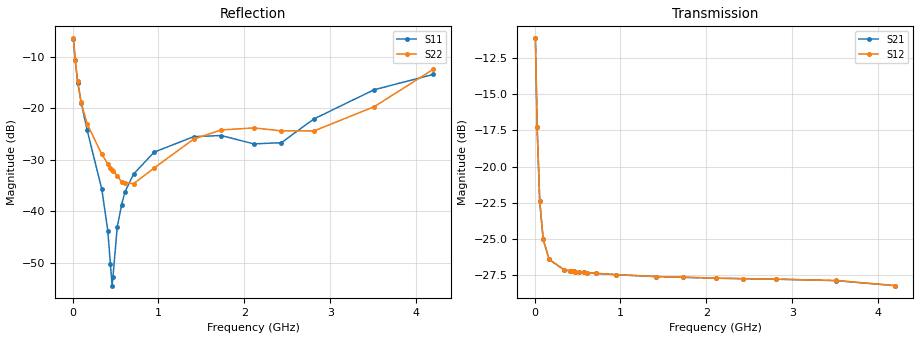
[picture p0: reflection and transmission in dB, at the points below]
! Integrated Device Technology
! Corporate Headquarters
! 6024 Silver Creek Valley Road
! San Jose, CA 95138  USA
! Phone:  1-408-284-8200
! Toll Free:  1-800-223-1366
! Webpage:  http://www.idt.com/
! Timing and RF Division
! 515 Groton Road, Suite 102
! Westford, MA 01886-6024
! Device:  F1950
! Description: 7-bit 0.25 dB Digital Step Attenuator
! Frequency:  150.0 -  4000.00 MHz
! Package:  4x4 mm Thin QFN Plastic Package: 24 pin
! Ports:  2 RF, 12 DC
!  Pin  1  = D0
!  Pin  2  = VDD
!  Pin  3  = Vmode
!  Pin  4  = GND
!  Pin  5  = RF1  =  Port 1
!  Pin  6  = GND
!  Pin  7  = GND
!  Pin  8  = GND
!  Pin  9  = GND
!  Pin 10  = GND
!  Pin 11  = GND
!  Pin 12  = GND
!  Pin 13  = GND
!  Pin 14  = RF2  =  Port 2
!  Pin 15  = GND
!  Pin 16  = LE
!  Pin 17  = CLK
!  Pin 18  = DATE
!  Pin 19  = D6
!  Pin 20  = D5
!  Pin 21  = D4
!  Pin 22  = D3
!  Pin 23  = D2
!  Pin 24  = D1
! State:  106
! Atten State:  26.50 dB
! Voltage:  +5.00 Volts
! Current:  Not Measured mA
! Data:  The device was measured on a the F195X evaluation board which has
!  individual transmission lines to the RF pins.  Data was collected
!  using a calibrated network analyzer.  The evaluation board was
!  de-embedded using a TRL calibration technique.
!  The reference plane is the edge of the package pin.
! Misc:  Board 2019
!  Action Tracker AT0250
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# GHz S dB R 50
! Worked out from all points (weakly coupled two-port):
!   420 points, 10 MHz to 4.2 GHz, reference 50 ohm
!   highest |S21| = -11.15 dB at 10 MHz (marker M1); lowest = -28.2 dB at 4.2 GHz (marker M2)
!   lowest |S11| = -54.4 dB at 460 MHz (marker M3), VSWR 1.00, Z = 49.8 - j0.079 ohm
!   |S11| at or under -10 dB: 26.72 MHz to end of sweep
!   |S22| runs from -34.9 to -6.5 dB; largest |S21 - S12| = 8.2e-05
!   S11 on the Smith chart (normalised r, x): 10 MHz: 2.02, -1.12; 30 MHz: 1.28, -0.64; 60 MHz: 1.11, -0.36; 410 MHz: 1.00, -0.01; 4.2 GHz: 0.68, +0.17
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0.01  -6.56 -27.3  -11.15 -36.1  -11.15 -36.1  -6.45 -28.4
0.03  -10.62 -50.4  -17.28 -55.1  -17.28 -55.1  -10.55 -52.0
0.06  -15.02 -63.5  -22.37 -50.2  -22.36 -50.2  -14.80 -65.1
0.1  -18.89 -70.4  -25.00 -38.4  -25.00 -38.4  -18.87 -70.8
0.17  -24.27 -72.1  -26.40 -26.4  -26.40 -26.4  -23.06 -76.7
0.34  -35.65 -71.6  -27.10 -16.9  -27.10 -16.9  -28.90 -85.6
0.41  -43.71 -80.3  -27.19 -15.5  -27.19 -15.5  -30.80 -88.8
0.44  -50.12 -101.8  -27.21 -15.1  -27.21 -15.2  -31.60 -92.9
0.46  -54.38 -155.5  -27.23 -14.9  -27.23 -15.0  -32.00 -96.3
0.47  -52.68 173.1  -27.24 -14.9  -27.24 -14.9  -32.15 -97.9
0.52  -43.02 142.3  -27.27 -14.5  -27.27 -14.6  -33.06 -102.8
0.57  -38.75 136.6  -27.30 -14.4  -27.29 -14.4  -34.28 -112.7
0.61  -36.17 137.8  -27.32 -14.3  -27.32 -14.3  -34.40 -120.9
0.71  -32.75 138.7  -27.36 -14.4  -27.35 -14.4  -34.62 -140.3
0.95  -28.49 146.7  -27.45 -15.4  -27.45 -15.4  -31.57 -176.4
1.41  -25.50 163.1  -27.58 -18.5  -27.58 -18.5  -25.97 160.9
1.73  -25.28 168.4  -27.63 -20.8  -27.63 -20.8  -24.20 152.4
2.11  -26.90 158.2  -27.69 -24.4  -27.69 -24.4  -23.80 142.7
2.43  -26.67 127.0  -27.73 -26.9  -27.72 -26.9  -24.38 132.0
2.81  -22.06 105.9  -27.76 -30.6  -27.76 -30.7  -24.39 116.8
3.51  -16.41 117.7  -27.86 -36.9  -27.85 -36.9  -19.71 113.7
4.2  -13.44 145.7  -28.21 -40.8  -28.20 -40.8  -12.44 127.3
